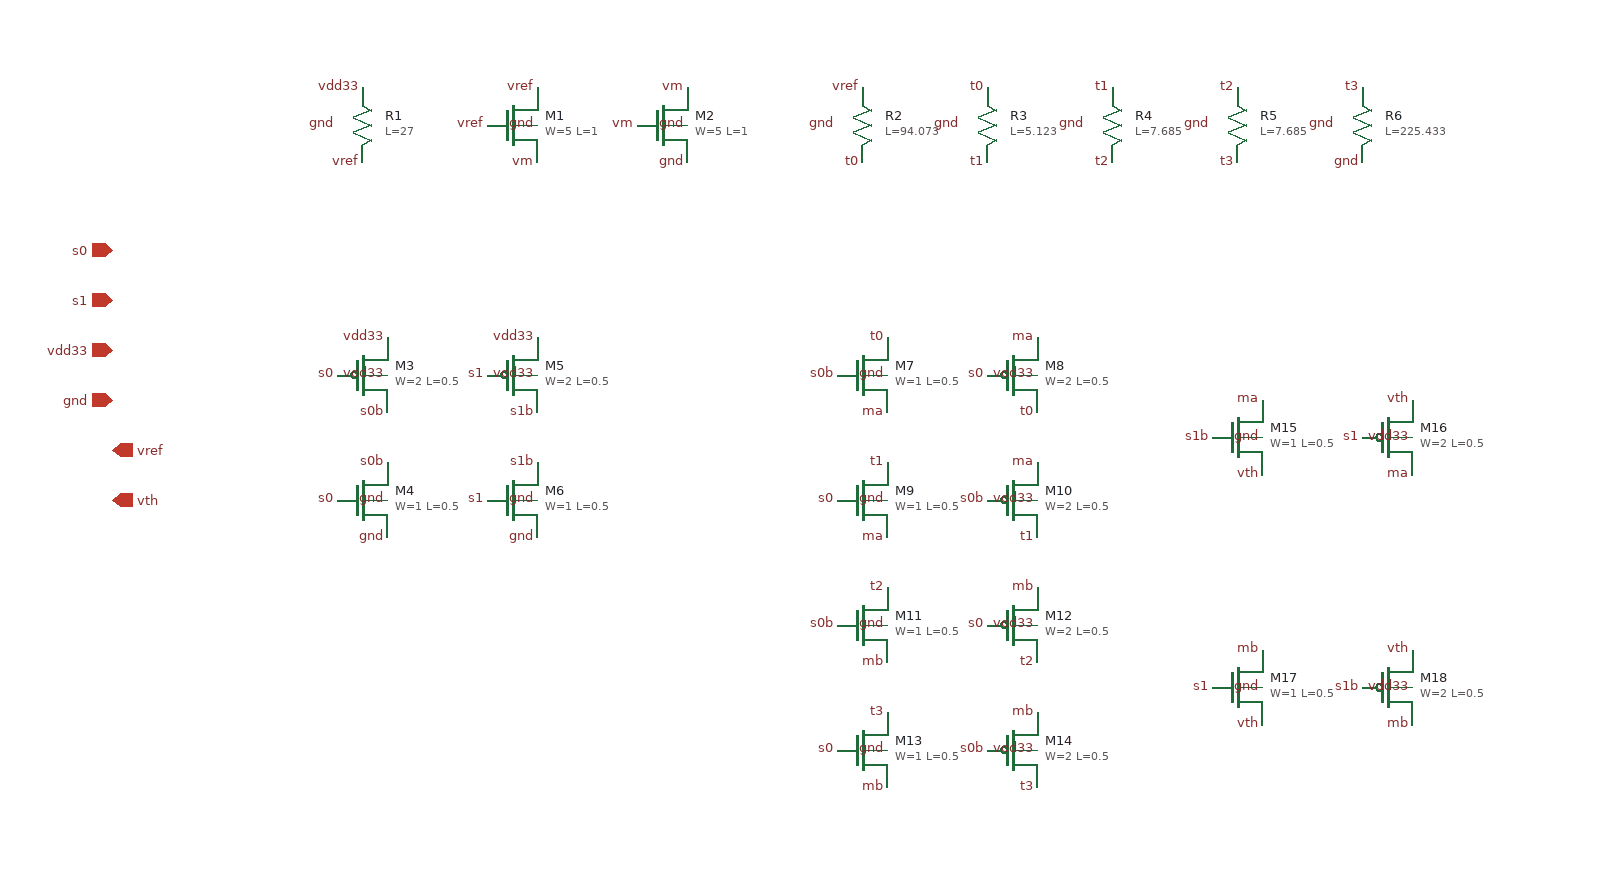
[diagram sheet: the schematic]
v {xschem version=3.4.7 file_version=1.2
}
G {}
K {}
V {}
S {}
E {}
C {sky130_fd_pr/res_xhigh_po_1p41.sym} 0 0 0 0 {name=R1 L=27 model=res_xhigh_po_1p41 spiceprefix=X mult=1}
C {devices/lab_pin.sym} 0 -30 0 0 {name=p1 sig_type=std_logic lab=vdd33}
C {devices/lab_pin.sym} 0 30 0 0 {name=p2 sig_type=std_logic lab=vref}
C {devices/lab_pin.sym} -20 0 0 0 {name=p3 sig_type=std_logic lab=gnd}
C {sky130_fd_pr/nfet_g5v0d10v5.sym} 120 0 0 0 {name=M1 L=1 W=5 nf=1 mult=1 model=nfet_g5v0d10v5 spiceprefix=X}
C {devices/lab_pin.sym} 140 -30 0 0 {name=p4 sig_type=std_logic lab=vref}
C {devices/lab_pin.sym} 100 0 0 0 {name=p5 sig_type=std_logic lab=vref}
C {devices/lab_pin.sym} 140 30 0 0 {name=p6 sig_type=std_logic lab=vm}
C {devices/lab_pin.sym} 140 0 0 0 {name=p7 sig_type=std_logic lab=gnd}
C {sky130_fd_pr/nfet_g5v0d10v5.sym} 240 0 0 0 {name=M2 L=1 W=5 nf=1 mult=1 model=nfet_g5v0d10v5 spiceprefix=X}
C {devices/lab_pin.sym} 260 -30 0 0 {name=p8 sig_type=std_logic lab=vm}
C {devices/lab_pin.sym} 220 0 0 0 {name=p9 sig_type=std_logic lab=vm}
C {devices/lab_pin.sym} 260 30 0 0 {name=p10 sig_type=std_logic lab=gnd}
C {devices/lab_pin.sym} 260 0 0 0 {name=p11 sig_type=std_logic lab=gnd}
C {sky130_fd_pr/res_xhigh_po_1p41.sym} 400 0 0 0 {name=R2 L=94.073 model=res_xhigh_po_1p41 spiceprefix=X mult=1}
C {devices/lab_pin.sym} 400 -30 0 0 {name=p12 sig_type=std_logic lab=vref}
C {devices/lab_pin.sym} 400 30 0 0 {name=p13 sig_type=std_logic lab=t0}
C {devices/lab_pin.sym} 380 0 0 0 {name=p14 sig_type=std_logic lab=gnd}
C {sky130_fd_pr/res_xhigh_po_1p41.sym} 500 0 0 0 {name=R3 L=5.123 model=res_xhigh_po_1p41 spiceprefix=X mult=1}
C {devices/lab_pin.sym} 500 -30 0 0 {name=p15 sig_type=std_logic lab=t0}
C {devices/lab_pin.sym} 500 30 0 0 {name=p16 sig_type=std_logic lab=t1}
C {devices/lab_pin.sym} 480 0 0 0 {name=p17 sig_type=std_logic lab=gnd}
C {sky130_fd_pr/res_xhigh_po_1p41.sym} 600 0 0 0 {name=R4 L=7.685 model=res_xhigh_po_1p41 spiceprefix=X mult=1}
C {devices/lab_pin.sym} 600 -30 0 0 {name=p18 sig_type=std_logic lab=t1}
C {devices/lab_pin.sym} 600 30 0 0 {name=p19 sig_type=std_logic lab=t2}
C {devices/lab_pin.sym} 580 0 0 0 {name=p20 sig_type=std_logic lab=gnd}
C {sky130_fd_pr/res_xhigh_po_1p41.sym} 700 0 0 0 {name=R5 L=7.685 model=res_xhigh_po_1p41 spiceprefix=X mult=1}
C {devices/lab_pin.sym} 700 -30 0 0 {name=p21 sig_type=std_logic lab=t2}
C {devices/lab_pin.sym} 700 30 0 0 {name=p22 sig_type=std_logic lab=t3}
C {devices/lab_pin.sym} 680 0 0 0 {name=p23 sig_type=std_logic lab=gnd}
C {sky130_fd_pr/res_xhigh_po_1p41.sym} 800 0 0 0 {name=R6 L=225.433 model=res_xhigh_po_1p41 spiceprefix=X mult=1}
C {devices/lab_pin.sym} 800 -30 0 0 {name=p24 sig_type=std_logic lab=t3}
C {devices/lab_pin.sym} 800 30 0 0 {name=p25 sig_type=std_logic lab=gnd}
C {devices/lab_pin.sym} 780 0 0 0 {name=p26 sig_type=std_logic lab=gnd}
C {sky130_fd_pr/pfet_g5v0d10v5.sym} 0 200 0 0 {name=M3 L=0.5 W=2 nf=1 mult=1 model=pfet_g5v0d10v5 spiceprefix=X}
C {devices/lab_pin.sym} 20 170 0 0 {name=p27 sig_type=std_logic lab=vdd33}
C {devices/lab_pin.sym} -20 200 0 0 {name=p28 sig_type=std_logic lab=s0}
C {devices/lab_pin.sym} 20 230 0 0 {name=p29 sig_type=std_logic lab=s0b}
C {devices/lab_pin.sym} 20 200 0 0 {name=p30 sig_type=std_logic lab=vdd33}
C {sky130_fd_pr/nfet_g5v0d10v5.sym} 0 300 0 0 {name=M4 L=0.5 W=1 nf=1 mult=1 model=nfet_g5v0d10v5 spiceprefix=X}
C {devices/lab_pin.sym} 20 270 0 0 {name=p31 sig_type=std_logic lab=s0b}
C {devices/lab_pin.sym} -20 300 0 0 {name=p32 sig_type=std_logic lab=s0}
C {devices/lab_pin.sym} 20 330 0 0 {name=p33 sig_type=std_logic lab=gnd}
C {devices/lab_pin.sym} 20 300 0 0 {name=p34 sig_type=std_logic lab=gnd}
C {sky130_fd_pr/pfet_g5v0d10v5.sym} 120 200 0 0 {name=M5 L=0.5 W=2 nf=1 mult=1 model=pfet_g5v0d10v5 spiceprefix=X}
C {devices/lab_pin.sym} 140 170 0 0 {name=p35 sig_type=std_logic lab=vdd33}
C {devices/lab_pin.sym} 100 200 0 0 {name=p36 sig_type=std_logic lab=s1}
C {devices/lab_pin.sym} 140 230 0 0 {name=p37 sig_type=std_logic lab=s1b}
C {devices/lab_pin.sym} 140 200 0 0 {name=p38 sig_type=std_logic lab=vdd33}
C {sky130_fd_pr/nfet_g5v0d10v5.sym} 120 300 0 0 {name=M6 L=0.5 W=1 nf=1 mult=1 model=nfet_g5v0d10v5 spiceprefix=X}
C {devices/lab_pin.sym} 140 270 0 0 {name=p39 sig_type=std_logic lab=s1b}
C {devices/lab_pin.sym} 100 300 0 0 {name=p40 sig_type=std_logic lab=s1}
C {devices/lab_pin.sym} 140 330 0 0 {name=p41 sig_type=std_logic lab=gnd}
C {devices/lab_pin.sym} 140 300 0 0 {name=p42 sig_type=std_logic lab=gnd}
C {sky130_fd_pr/nfet_g5v0d10v5.sym} 400 200 0 0 {name=M7 L=0.5 W=1 nf=1 mult=1 model=nfet_g5v0d10v5 spiceprefix=X}
C {devices/lab_pin.sym} 420 170 0 0 {name=p43 sig_type=std_logic lab=t0}
C {devices/lab_pin.sym} 380 200 0 0 {name=p44 sig_type=std_logic lab=s0b}
C {devices/lab_pin.sym} 420 230 0 0 {name=p45 sig_type=std_logic lab=ma}
C {devices/lab_pin.sym} 420 200 0 0 {name=p46 sig_type=std_logic lab=gnd}
C {sky130_fd_pr/pfet_g5v0d10v5.sym} 520 200 0 0 {name=M8 L=0.5 W=2 nf=1 mult=1 model=pfet_g5v0d10v5 spiceprefix=X}
C {devices/lab_pin.sym} 540 170 0 0 {name=p47 sig_type=std_logic lab=ma}
C {devices/lab_pin.sym} 500 200 0 0 {name=p48 sig_type=std_logic lab=s0}
C {devices/lab_pin.sym} 540 230 0 0 {name=p49 sig_type=std_logic lab=t0}
C {devices/lab_pin.sym} 540 200 0 0 {name=p50 sig_type=std_logic lab=vdd33}
C {sky130_fd_pr/nfet_g5v0d10v5.sym} 400 300 0 0 {name=M9 L=0.5 W=1 nf=1 mult=1 model=nfet_g5v0d10v5 spiceprefix=X}
C {devices/lab_pin.sym} 420 270 0 0 {name=p51 sig_type=std_logic lab=t1}
C {devices/lab_pin.sym} 380 300 0 0 {name=p52 sig_type=std_logic lab=s0}
C {devices/lab_pin.sym} 420 330 0 0 {name=p53 sig_type=std_logic lab=ma}
C {devices/lab_pin.sym} 420 300 0 0 {name=p54 sig_type=std_logic lab=gnd}
C {sky130_fd_pr/pfet_g5v0d10v5.sym} 520 300 0 0 {name=M10 L=0.5 W=2 nf=1 mult=1 model=pfet_g5v0d10v5 spiceprefix=X}
C {devices/lab_pin.sym} 540 270 0 0 {name=p55 sig_type=std_logic lab=ma}
C {devices/lab_pin.sym} 500 300 0 0 {name=p56 sig_type=std_logic lab=s0b}
C {devices/lab_pin.sym} 540 330 0 0 {name=p57 sig_type=std_logic lab=t1}
C {devices/lab_pin.sym} 540 300 0 0 {name=p58 sig_type=std_logic lab=vdd33}
C {sky130_fd_pr/nfet_g5v0d10v5.sym} 400 400 0 0 {name=M11 L=0.5 W=1 nf=1 mult=1 model=nfet_g5v0d10v5 spiceprefix=X}
C {devices/lab_pin.sym} 420 370 0 0 {name=p59 sig_type=std_logic lab=t2}
C {devices/lab_pin.sym} 380 400 0 0 {name=p60 sig_type=std_logic lab=s0b}
C {devices/lab_pin.sym} 420 430 0 0 {name=p61 sig_type=std_logic lab=mb}
C {devices/lab_pin.sym} 420 400 0 0 {name=p62 sig_type=std_logic lab=gnd}
C {sky130_fd_pr/pfet_g5v0d10v5.sym} 520 400 0 0 {name=M12 L=0.5 W=2 nf=1 mult=1 model=pfet_g5v0d10v5 spiceprefix=X}
C {devices/lab_pin.sym} 540 370 0 0 {name=p63 sig_type=std_logic lab=mb}
C {devices/lab_pin.sym} 500 400 0 0 {name=p64 sig_type=std_logic lab=s0}
C {devices/lab_pin.sym} 540 430 0 0 {name=p65 sig_type=std_logic lab=t2}
C {devices/lab_pin.sym} 540 400 0 0 {name=p66 sig_type=std_logic lab=vdd33}
C {sky130_fd_pr/nfet_g5v0d10v5.sym} 400 500 0 0 {name=M13 L=0.5 W=1 nf=1 mult=1 model=nfet_g5v0d10v5 spiceprefix=X}
C {devices/lab_pin.sym} 420 470 0 0 {name=p67 sig_type=std_logic lab=t3}
C {devices/lab_pin.sym} 380 500 0 0 {name=p68 sig_type=std_logic lab=s0}
C {devices/lab_pin.sym} 420 530 0 0 {name=p69 sig_type=std_logic lab=mb}
C {devices/lab_pin.sym} 420 500 0 0 {name=p70 sig_type=std_logic lab=gnd}
C {sky130_fd_pr/pfet_g5v0d10v5.sym} 520 500 0 0 {name=M14 L=0.5 W=2 nf=1 mult=1 model=pfet_g5v0d10v5 spiceprefix=X}
C {devices/lab_pin.sym} 540 470 0 0 {name=p71 sig_type=std_logic lab=mb}
C {devices/lab_pin.sym} 500 500 0 0 {name=p72 sig_type=std_logic lab=s0b}
C {devices/lab_pin.sym} 540 530 0 0 {name=p73 sig_type=std_logic lab=t3}
C {devices/lab_pin.sym} 540 500 0 0 {name=p74 sig_type=std_logic lab=vdd33}
C {sky130_fd_pr/nfet_g5v0d10v5.sym} 700 250 0 0 {name=M15 L=0.5 W=1 nf=1 mult=1 model=nfet_g5v0d10v5 spiceprefix=X}
C {devices/lab_pin.sym} 720 220 0 0 {name=p75 sig_type=std_logic lab=ma}
C {devices/lab_pin.sym} 680 250 0 0 {name=p76 sig_type=std_logic lab=s1b}
C {devices/lab_pin.sym} 720 280 0 0 {name=p77 sig_type=std_logic lab=vth}
C {devices/lab_pin.sym} 720 250 0 0 {name=p78 sig_type=std_logic lab=gnd}
C {sky130_fd_pr/pfet_g5v0d10v5.sym} 820 250 0 0 {name=M16 L=0.5 W=2 nf=1 mult=1 model=pfet_g5v0d10v5 spiceprefix=X}
C {devices/lab_pin.sym} 840 220 0 0 {name=p79 sig_type=std_logic lab=vth}
C {devices/lab_pin.sym} 800 250 0 0 {name=p80 sig_type=std_logic lab=s1}
C {devices/lab_pin.sym} 840 280 0 0 {name=p81 sig_type=std_logic lab=ma}
C {devices/lab_pin.sym} 840 250 0 0 {name=p82 sig_type=std_logic lab=vdd33}
C {sky130_fd_pr/nfet_g5v0d10v5.sym} 700 450 0 0 {name=M17 L=0.5 W=1 nf=1 mult=1 model=nfet_g5v0d10v5 spiceprefix=X}
C {devices/lab_pin.sym} 720 420 0 0 {name=p83 sig_type=std_logic lab=mb}
C {devices/lab_pin.sym} 680 450 0 0 {name=p84 sig_type=std_logic lab=s1}
C {devices/lab_pin.sym} 720 480 0 0 {name=p85 sig_type=std_logic lab=vth}
C {devices/lab_pin.sym} 720 450 0 0 {name=p86 sig_type=std_logic lab=gnd}
C {sky130_fd_pr/pfet_g5v0d10v5.sym} 820 450 0 0 {name=M18 L=0.5 W=2 nf=1 mult=1 model=pfet_g5v0d10v5 spiceprefix=X}
C {devices/lab_pin.sym} 840 420 0 0 {name=p87 sig_type=std_logic lab=vth}
C {devices/lab_pin.sym} 800 450 0 0 {name=p88 sig_type=std_logic lab=s1b}
C {devices/lab_pin.sym} 840 480 0 0 {name=p89 sig_type=std_logic lab=mb}
C {devices/lab_pin.sym} 840 450 0 0 {name=p90 sig_type=std_logic lab=vdd33}
C {devices/ipin.sym} -200 100 0 0 {name=p91 lab=s0}
C {devices/ipin.sym} -200 140 0 0 {name=p92 lab=s1}
C {devices/iopin.sym} -200 180 0 0 {name=p93 lab=vdd33}
C {devices/iopin.sym} -200 220 0 0 {name=p94 lab=gnd}
C {devices/opin.sym} -200 260 0 0 {name=p95 lab=vref}
C {devices/opin.sym} -200 300 0 0 {name=p96 lab=vth}
